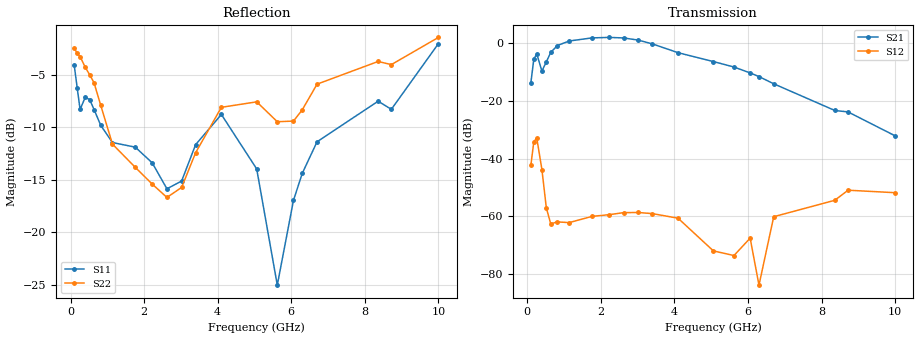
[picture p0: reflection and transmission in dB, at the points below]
! Integrated Device Technology
! Corporate Headquarters
! 6024 Silver Creek Valley Road
! San Jose, CA 95138  USA
! Phone:  1-408-284-8200
! Toll Free:  1-800-223-1366
! Webpage:  http://www.idt.com/
! Timing and RF Division
! 515 Groton Road, Suite 102
! Westford, MA 01886-6024
! Device:  F1456
! Description: 6-bit 0.5 dB Transmit Variable Gain Amplifier
! Frequency:  2100.0 -  2950.00 MHz
! Package:  6x6 mm Thin QFN Plastic Package: 28 pin
! State:  60
! Atten State:  30.0 dB
! Voltage:  +5.00 Volts
! Current:  216.949 mA
! Data:  The device was measured on a the F1455 evaluation board which has
!  individual transmission lines to the RF pins.  Data was collected
!  using a calibrated network analyzer.  The evaluation board was
!  de-embedded using a TRL calibration technique.
!  The reference plane is the edge of the package pin.
!  Pin  1 = CSb
!  Pin  2 = DATA
!  Pin  3 = CLK
!  Pin  4 = RSET
!  Pin  5 = GND
!  Pin  6 = RFIN  = Port 1
!  Pin  7 = GND
!  Pin  8 = NC
!  Pin  9 = NC
!  Pin 10 = NC
!  Pin 11 = NC
!  Pin 12 = NC
!  Pin 13 = NC
!  Pin 14 = /STBY
!  Pin 15 = GND
!  Pin 16 = RFOUT  = Port 2
!  Pin 17 = GND
!  Pin 18 = NC
!  Pin 19 = NC
!  Pin 20 = NC
!  Pin 21 = GND
!  Pin 22 = NC
!  Pin 23 = GND
!  Pin 24 = NC
!  Pin 25 = NC
!  Pin 26 = NC
!  Pin 27 = GND
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# GHz S dB R 50
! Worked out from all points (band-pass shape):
!   496 points, 100 MHz to 10 GHz, reference 50 ohm
!   highest |S21| = 2.06 dB at 2.22 GHz (marker M1); lowest = -32.1 dB at 10 GHz (marker M2)
!   |S21| within 3 dB of the highest: 800.1 MHz to 3.576 GHz (2.776 GHz wide, 127 % of centre)
!   lowest |S11| = -25.0 dB at 5.62 GHz (marker M3), VSWR 1.12, Z = 53.1 + j4.89 ohm
!   |S11| at or under -10 dB: 847.3 MHz to 3.655 GHz (2.807 GHz wide, 125 % of centre); 4.634 GHz to 7.071 GHz (2.438 GHz wide, 41.6 % of centre)
!   |S22| runs from -16.8 to -1.5 dB; largest |S21 - S12| = 1.3
!   S11 on the Smith chart (normalised r, x): 100 MHz: 2.37, -2.04; 640 MHz: 1.04, -0.84; 3.02 GHz: 0.75, +0.19; 6.06 GHz: 1.32, +0.08; 8.72 GHz: 0.90, +0.78; 10 GHz: 4.19, +4.17
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0.1  -4.10 -24.9  -13.71 -150.9  -42.32 50.5  -2.51 140.8
0.18  -6.24 -40.3  -5.50 159.0  -34.18 -2.3  -2.97 109.7
0.26  -8.32 -28.4  -3.65 60.1  -32.89 -100.7  -3.30 88.7
0.4  -7.17 -33.8  -9.64 -94.3  -43.81 148.6  -4.31 44.7
0.52  -7.38 -50.6  -6.43 162.7  -57.11 114.1  -5.02 19.7
0.64  -8.33 -65.1  -3.17 110.0  -62.69 137.8  -5.79 -8.0
0.82  -9.83 -83.2  -0.77 57.9  -61.99 118.7  -7.92 -46.4
1.14  -11.47 -109.4  0.80 -2.3  -62.25 87.2  -11.62 -92.1
1.76  -11.91 -137.5  1.88 -85.1  -60.09 53.8  -13.83 -132.1
2.22  -13.40 -152.2  2.06 -137.1  -59.50 39.3  -15.42 -142.5
2.62  -15.87 -178.6  1.87 178.8  -58.79 25.7  -16.69 -156.7
3.02  -15.13 136.4  1.11 135.4  -58.73 8.5  -15.74 173.0
3.4  -11.67 114.5  -0.19 96.6  -59.12 -6.8  -12.44 147.9
4.1  -8.80 112.1  -3.25 36.1  -60.72 -40.8  -8.12 133.3
5.06  -13.98 119.7  -6.33 -38.3  -72.06 -88.1  -7.60 135.1
5.62  -25.03 55.0  -8.23 -86.6  -73.68 139.6  -9.49 119.3
6.06  -16.96 12.6  -10.28 -127.5  -67.64 124.3  -9.43 89.2
6.3  -14.39 19.5  -11.54 -149.7  -83.95 122.8  -8.35 75.2
6.7  -11.40 39.5  -14.05 173.0  -60.20 137.8  -5.92 63.6
8.36  -7.54 89.5  -23.31 55.4  -54.50 50.8  -3.76 62.5
8.72  -8.31 74.7  -23.82 26.6  -51.00 59.3  -4.06 50.3
10  -2.06 13.8  -32.12 -77.4  -51.86 -31.5  -1.47 -2.6
